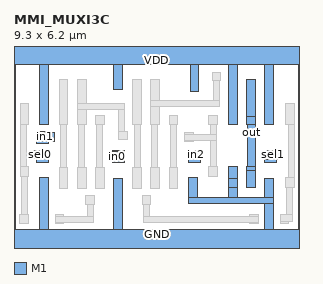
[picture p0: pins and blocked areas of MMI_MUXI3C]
MACRO MMI_MUXI3C
	CLASS CORE ;
	FOREIGN MMI_MUXI3C 0 0 ;
	SIZE 9.3 BY 6.2 ;
	SYMMETRY X Y ;
	SITE CORE1 ;
	PIN out
		DIRECTION output ;
		USE SIGNAL ;
		PORT
			LAYER M1 ;
			RECT 7.6 4.1 7.88 5.29 ;
			LAYER M1 ;
			RECT 7.6 3.82 7.89 4.1 ;
			LAYER M1 ;
			RECT 7.605 2.475 7.89 3.82 ;
			LAYER M1 ;
			RECT 7.6 2.34 7.89 2.475 ;
			LAYER M1 ;
			RECT 7.6 1.78 7.88 2.34 ;
		END
		AntennaDiffArea 1.0142 ;
	END out
	PIN in1
		DIRECTION input ;
		USE SIGNAL ;
		PORT
			LAYER M1 ;
			RECT 0.74 3.57 1.12 3.6 ;
			LAYER M1 ;
			RECT 0.74 3.29 1.31 3.57 ;
			LAYER M1 ;
			RECT 0.74 3.22 1.12 3.29 ;
		END
		AntennaGateArea 0.34575 ;
	END in1
	PIN sel0
		DIRECTION input ;
		USE SIGNAL ;
		PORT
			LAYER M1 ;
			RECT 0.605 2.98 0.885 2.99 ;
			LAYER M1 ;
			RECT 0.605 2.71 1.12 2.98 ;
			LAYER M1 ;
			RECT 0.74 2.6 1.12 2.71 ;
		END
		AntennaGateArea 0.51975 ;
	END sel0
	PIN GND
		DIRECTION inout ;
		USE GROUND ;
		PORT
			LAYER M1 ;
			RECT 0.84 0.42 1.12 2.12 ;
			LAYER M1 ;
			RECT 3.25 0.42 3.53 2.065 ;
			LAYER M1 ;
			RECT 5.705 1.445 5.99 2.12 ;
			LAYER M1 ;
			RECT 7.01 2.065 7.29 2.475 ;
			LAYER M1 ;
			RECT 7 1.78 7.29 2.065 ;
			LAYER M1 ;
			RECT 7 1.445 7.285 1.78 ;
			LAYER M1 ;
			RECT 8.19 1.445 8.47 2.065 ;
			LAYER M1 ;
			RECT 5.705 1.255 8.47 1.445 ;
			LAYER M1 ;
			RECT 8.19 0.42 8.47 1.255 ;
			LAYER M1 ;
			RECT 0 -0.42 9.3 0.42 ;
		END
	END GND
	PIN in2
		DIRECTION input ;
		USE SIGNAL ;
		PORT
			LAYER M1 ;
			RECT 5.895 2.98 6.175 2.99 ;
			LAYER M1 ;
			RECT 5.7 2.71 6.175 2.98 ;
			LAYER M1 ;
			RECT 5.7 2.6 6.08 2.71 ;
		END
		AntennaGateArea 0.17325 ;
	END in2
	PIN sel1
		DIRECTION input ;
		USE SIGNAL ;
		PORT
			LAYER M1 ;
			RECT 8.18 2.7 8.715 2.98 ;
			LAYER M1 ;
			RECT 8.18 2.6 8.56 2.7 ;
		END
		AntennaGateArea 0.51975 ;
	END sel1
	PIN VDD
		DIRECTION inout ;
		USE POWER ;
		PORT
			LAYER M1 ;
			RECT 0 5.78 9.3 6.62 ;
			LAYER M1 ;
			RECT 0.84 3.835 1.12 5.78 ;
			LAYER M1 ;
			RECT 3.25 4.965 3.53 5.78 ;
			LAYER M1 ;
			RECT 5.75 4.91 6.03 5.78 ;
			LAYER M1 ;
			RECT 7.01 3.82 7.29 5.78 ;
			LAYER M1 ;
			RECT 8.19 3.82 8.47 5.78 ;
		END
	END VDD
	PIN in0
		DIRECTION input ;
		USE SIGNAL ;
		PORT
			LAYER M1 ;
			RECT 3.22 2.94 3.6 2.98 ;
			LAYER M1 ;
			RECT 3.09 2.66 3.6 2.94 ;
			LAYER M1 ;
			RECT 3.22 2.6 3.6 2.66 ;
		END
		AntennaGateArea 0.3465 ;
	END in0
	OBS
		LAYER M1 ;
		RECT 0.205 3.835 0.485 4.535 ;
		LAYER M1 ;
		RECT 1.48 3.835 1.76 5.305 ;
		LAYER M1 ;
		RECT 2.07 4.52 2.35 5.305 ;
		LAYER M1 ;
		RECT 2.07 4.325 3.615 4.52 ;
		LAYER M1 ;
		RECT 2.07 3.835 2.35 4.325 ;
		LAYER M1 ;
		RECT 2.66 3.835 2.94 4.115 ;
		LAYER M1 ;
		RECT 0.205 2.465 0.4 3.835 ;
		LAYER M1 ;
		RECT 0.205 2.15 0.485 2.465 ;
		LAYER M1 ;
		RECT 1.525 2.44 1.715 3.835 ;
		LAYER M1 ;
		RECT 2.115 2.44 2.31 3.835 ;
		LAYER M1 ;
		RECT 2.7 2.44 2.89 3.835 ;
		LAYER M1 ;
		RECT 3.425 3.62 3.615 4.325 ;
		LAYER M1 ;
		RECT 3.87 3.835 4.15 5.305 ;
		LAYER M1 ;
		RECT 4.46 4.615 4.74 5.305 ;
		LAYER M1 ;
		RECT 6.525 5.535 6.715 5.54 ;
		LAYER M1 ;
		RECT 6.47 5.255 6.75 5.535 ;
		LAYER M1 ;
		RECT 6.525 4.615 6.715 5.255 ;
		LAYER M1 ;
		RECT 4.46 4.42 6.715 4.615 ;
		LAYER M1 ;
		RECT 4.46 3.835 4.74 4.42 ;
		LAYER M1 ;
		RECT 5.06 3.835 5.34 4.115 ;
		LAYER M1 ;
		RECT 6.355 3.835 6.635 4.115 ;
		LAYER M1 ;
		RECT 3.425 3.34 3.705 3.62 ;
		LAYER M1 ;
		RECT 3.92 2.44 4.115 3.835 ;
		LAYER M1 ;
		RECT 4.5 2.44 4.69 3.835 ;
		LAYER M1 ;
		RECT 5.1 2.44 5.295 3.835 ;
		LAYER M1 ;
		RECT 5.575 3.52 5.855 3.57 ;
		LAYER M1 ;
		RECT 6.42 3.52 6.61 3.835 ;
		LAYER M1 ;
		RECT 8.86 3.82 9.14 4.52 ;
		LAYER M1 ;
		RECT 5.575 3.325 6.61 3.52 ;
		LAYER M1 ;
		RECT 5.575 3.29 5.855 3.325 ;
		LAYER M1 ;
		RECT 6.42 2.465 6.61 3.325 ;
		LAYER M1 ;
		RECT 0.255 0.9 0.45 2.15 ;
		LAYER M1 ;
		RECT 0.19 0.62 0.47 0.9 ;
		LAYER M1 ;
		RECT 1.48 1.74 1.76 2.44 ;
		LAYER M1 ;
		RECT 2.07 1.74 2.35 2.44 ;
		LAYER M1 ;
		RECT 2.66 1.74 2.94 2.44 ;
		LAYER M1 ;
		RECT 2.345 1.23 2.625 1.51 ;
		LAYER M1 ;
		RECT 1.35 0.84 1.63 0.9 ;
		LAYER M1 ;
		RECT 2.395 0.84 2.585 1.23 ;
		LAYER M1 ;
		RECT 1.35 0.65 2.585 0.84 ;
		LAYER M1 ;
		RECT 1.35 0.62 1.63 0.65 ;
		LAYER M1 ;
		RECT 3.87 1.74 4.15 2.44 ;
		LAYER M1 ;
		RECT 4.46 1.74 4.74 2.44 ;
		LAYER M1 ;
		RECT 5.06 1.74 5.34 2.44 ;
		LAYER M1 ;
		RECT 6.355 2.15 6.635 2.465 ;
		LAYER M1 ;
		RECT 4.18 1.23 4.46 1.51 ;
		LAYER M1 ;
		RECT 8.945 2.095 9.14 3.82 ;
		LAYER M1 ;
		RECT 8.86 1.78 9.14 2.095 ;
		LAYER M1 ;
		RECT 4.22 0.84 4.41 1.23 ;
		LAYER M1 ;
		RECT 7.695 0.84 7.975 0.9 ;
		LAYER M1 ;
		RECT 4.22 0.65 7.975 0.84 ;
		LAYER M1 ;
		RECT 7.695 0.62 7.975 0.65 ;
		LAYER M1 ;
		RECT 8.885 0.9 9.08 1.78 ;
		LAYER M1 ;
		RECT 8.69 0.66 9.08 0.9 ;
		LAYER M1 ;
		RECT 8.69 0.62 8.97 0.66 ;
	END
END MMI_MUXI3C
